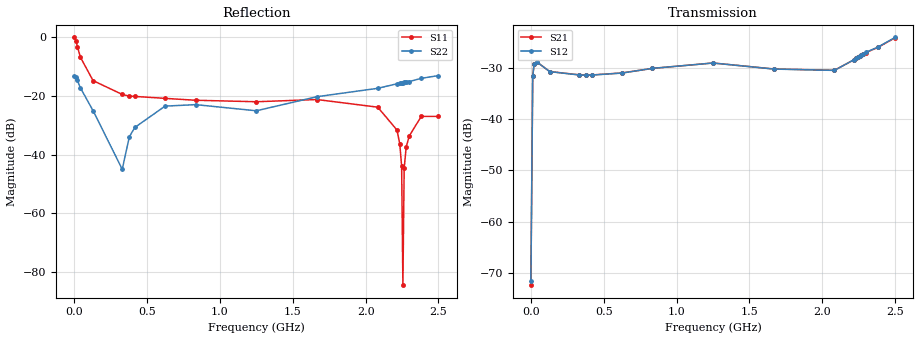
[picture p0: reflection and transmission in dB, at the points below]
#  HZ  S  MA  R  50.00
! Rohde & Schwarz Vector Network Analyzer
! Rohde-Schwarz,ZNL6-2Port,1323001206101378,1.50.1.34-21.10.1.104
! Created: UTC 3/3/2025, 5:15:16 AM
! freq[Hz]  mag:S11  ang:S11  mag:S21  ang:S21  mag:S12  ang:S12  mag:S22  ang:S22
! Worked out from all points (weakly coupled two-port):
!   10001 points, 5 kHz to 2.5 GHz, reference 50 ohm
!   highest |S21| = -24.21 dB at 2.5 GHz (marker M1); lowest = -72.3 dB at 5 kHz (marker M2)
!   lowest |S11| = -84.4 dB at 2.256 GHz (marker M3), VSWR 1.00, Z = 50 + j0.00599 ohm
!   |S11| at or under -10 dB: 66.51 MHz to end of sweep
!   |S22| runs from -45.3 to -12.8 dB; largest |S21 - S12| = 0.0083
!   S11 on the Smith chart (normalised r, x): 5 kHz: 0.00, -0.00; 12.75 MHz: 0.09, +0.29; 42.25 MHz: 0.52, +0.56; 2.5 GHz: 0.92, -0.02
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5000  0.9939 -179.6  0.0002418 -22.5  0.0002644 -13.9  0.2228 -177.9
1.275497e7  0.8471 147.3  0.02617 -133.7  0.02611 -133.7  0.2067 152.9
2.225496e7  0.6883 130.9  0.03419 -156.2  0.03415 -156.2  0.1836 135.2
4.225492e7  0.4586 110.1  0.03579 177.3  0.03577 175.6  0.1377 104.3
1.292547e8  0.1825 79.1  0.02895 143.9  0.02888 143.1  0.05622 34.3
3.297543e8  0.1061 46.7  0.02689 101.5  0.02681 100.1  0.00564 -161.9
3.787542e8  0.0992 37.2  0.02678 91.4  0.02672 90.1  0.02031 119.6
4.167542e8  0.09814 32.1  0.02678 84.3  0.02672 82.8  0.02915 112.6
6.237538e8  0.09094 4.7  0.02802 51.5  0.02794 48.9  0.06709 48.9
8.335033e8  0.08442 -17.0  0.03101 19.5  0.03106 18.1  0.07111 4.2
1.250002e9  0.07967 -70.4  0.03505 -42.2  0.03501 -43.6  0.05588 -23.1
1.666752e9  0.08685 -139.8  0.03065 -91.6  0.03058 -92.4  0.09717 -78.4
2.083501e9  0.06434 149.3  0.02975 -106.3  0.02968 -106.5  0.1349 -157.3
2.215001e9  0.02632 102.6  0.0375 -109.7  0.03756 -110.0  0.161 179.7
2.234501e9  0.01527 109.4  0.03925 -111.0  0.0391 -111.4  0.1651 176.1
2.247251e9  0.006375 114.1  0.04037 -112.1  0.04015 -112.3  0.1678 174.0
2.256e9  5.997e-05 92.6  0.04107 -112.9  0.04089 -113.1  0.1693 172.7
2.26475e9  0.005817 -60.6  0.04171 -113.8  0.04159 -113.8  0.1707 171.3
2.2785e9  0.01362 -58.3  0.04261 -115.2  0.04275 -115.0  0.1726 169.0
2.3005e9  0.02095 -60.6  0.04426 -117.1  0.04458 -117.1  0.1759 164.9
2.382e9  0.04486 -114.4  0.04972 -125.1  0.05002 -125.1  0.1994 154.0
2.5e9  0.04476 -162.5  0.06159 -130.6  0.06218 -131.1  0.2223 133.3
